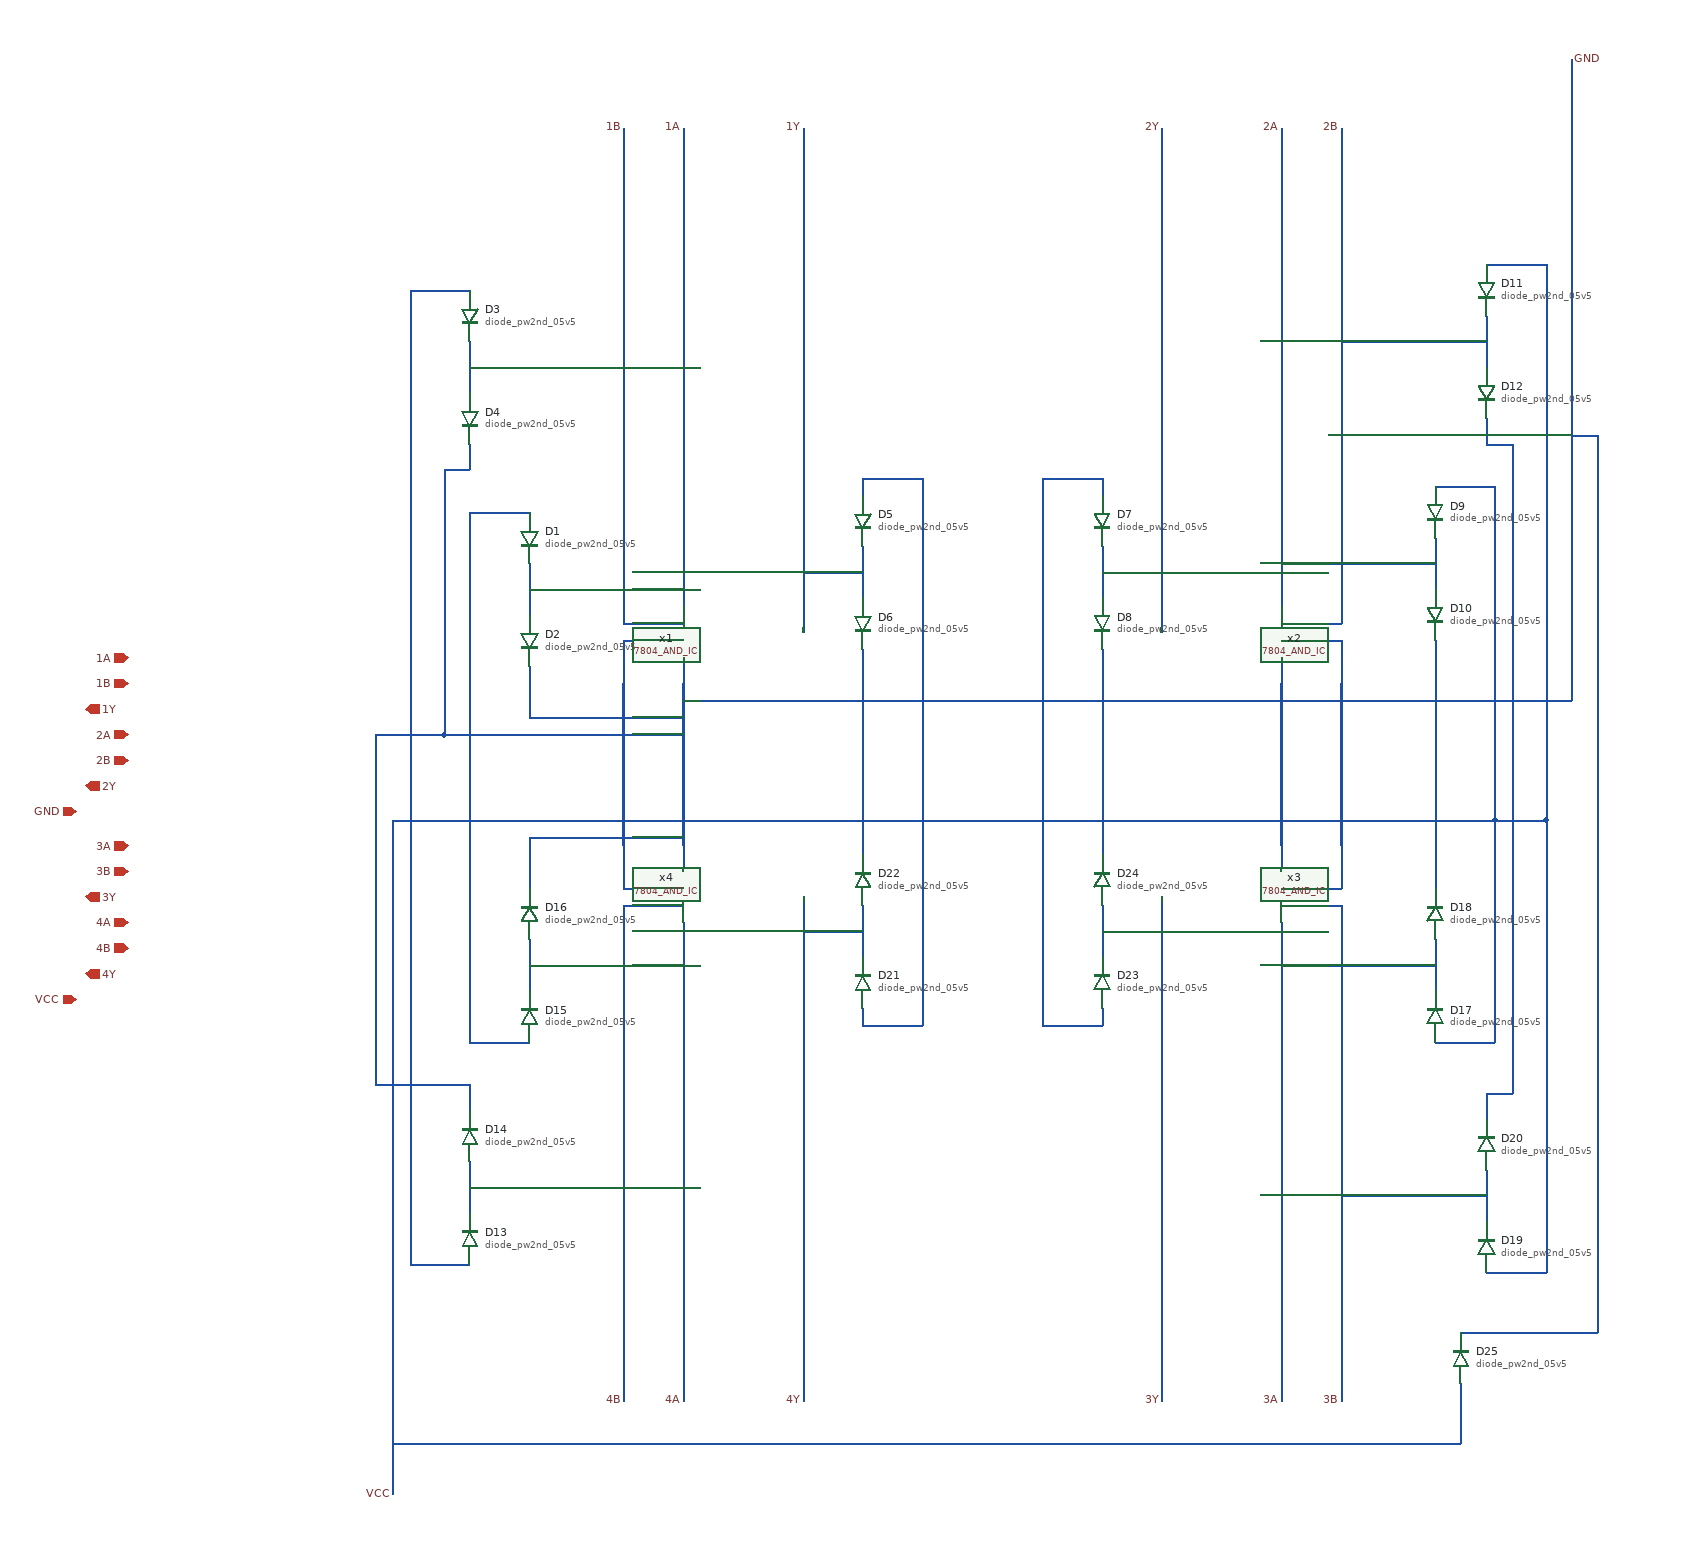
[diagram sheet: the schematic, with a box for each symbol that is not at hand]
v {xschem version=3.4.5 file_version=1.2
}
G {}
K {}
V {}
S {}
E {}
N -590 -970 -590 -520 {
lab=1A}
N -660 -500 -640 -500 {
lab=1B}
N -660 -970 -660 -500 {
lab=1B}
N -450 -970 -450 -490 {
lab=1Y}
N -590 -460 -590 -430 {
lab=GND}
N -660 -480 -640 -480 {
lab=VCC}
N -660 -480 -660 -430 {
lab=VCC}
N 110 -970 110 -520 {
lab=2A}
N 110 -500 180 -500 {
lab=2B}
N 180 -970 180 -500 {
lab=2B}
N 110 -460 110 -430 {
lab=GND}
N 110 -480 180 -480 {
lab=VCC}
N 180 -480 180 -430 {
lab=VCC}
N -30 -970 -30 -490 {
lab=2Y}
N 110 -240 110 -210 {
lab=GND}
N 110 -190 180 -190 {
lab=VCC}
N 180 -240 180 -190 {
lab=VCC}
N 110 -150 110 -120 {
lab=3A}
N 180 -170 180 -120 {
lab=3B}
N 110 -170 180 -170 {
lab=3B}
N -30 -180 -30 -120 {
lab=3Y}
N -450 -180 -450 300 {
lab=4Y}
N -590 -240 -590 -210 {
lab=GND}
N -660 -190 -640 -190 {
lab=VCC}
N -660 -240 -660 -190 {
lab=VCC}
N -590 -150 -590 300 {
lab=4A}
N -660 -170 -640 -170 {
lab=4B}
N -660 -170 -660 300 {
lab=4B}
N -590 -430 -590 -240 {bus=true
lab=GND}
N -660 -430 -660 -240 {bus=true
lab=VCC}
N 110 -430 110 -240 {bus=true
lab=GND}
N 180 -430 180 -240 {bus=true
lab=VCC}
N -930 -270 -930 300 {
lab=VCC}
N -930 -270 -870 -270 {
lab=VCC}
N 110 -410 250 -410 {
lab=GND}
N 450 -970 450 -410 {
lab=GND}
N -660 -1080 -660 -970 {
lab=1B}
N -590 -1080 -590 -970 {
lab=1A}
N -450 -1080 -450 -970 {
lab=1Y}
N -30 -1080 -30 -970 {
lab=2Y}
N 110 -1080 110 -970 {
lab=2A}
N 180 -1080 180 -970 {
lab=2B}
N 450 -1080 450 -970 {
lab=GND}
N -930 300 -930 410 {
lab=VCC}
N -660 300 -660 410 {
lab=4B}
N -590 300 -590 410 {
lab=4A}
N -450 300 -450 410 {
lab=4Y}
N -30 -120 -30 410 {
lab=3Y}
N 110 -120 110 410 {
lab=3A}
N 180 -120 180 410 {
lab=3B}
N -640 -500 -610 -500 {
lab=1B}
N -640 -480 -610 -480 {
lab=VCC}
N -640 -190 -610 -190 {
lab=VCC}
N -640 -170 -610 -170 {
lab=4B}
N -610 -500 -590 -500 {
lab=1B}
N -610 -480 -590 -480 {
lab=VCC}
N -610 -190 -590 -190 {
lab=VCC}
N -610 -170 -590 -170 {
lab=4B}
N -870 -270 -660 -270 {
lab=VCC}
N -660 -270 180 -270 {
lab=VCC}
N -590 -410 110 -410 {
lab=GND}
N -770 -570 -770 -510 {
lab=1A}
N -770 -540 -590 -540 {
lab=1A}
N -770 -450 -770 -390 {
lab=GND}
N -770 -390 -590 -390 {
lab=GND}
N -840 -630 -770 -630 {
lab=VCC}
N -840 -630 -840 -270 {
lab=VCC}
N -840 -830 -840 -770 {
lab=1B}
N -840 -800 -660 -800 {
lab=1B}
N -910 -890 -840 -890 {
lab=VCC}
N -910 -890 -910 -530 {
lab=VCC}
N -910 -530 -910 -270 {
lab=VCC}
N -840 -710 -840 -680 {
lab=GND}
N -870 -680 -840 -680 {
lab=GND}
N -870 -680 -870 -370 {
lab=GND}
N -380 -590 -380 -530 {
lab=1Y}
N -380 -470 -380 -410 {
lab=GND}
N -380 -670 -380 -650 {
lab=VCC}
N -380 -670 -310 -670 {
lab=VCC}
N -310 -670 -310 -270 {
lab=VCC}
N -100 -590 -100 -530 {
lab=2Y}
N -100 -470 -100 -410 {
lab=GND}
N -100 -670 -100 -650 {
lab=VCC}
N -170 -670 -100 -670 {
lab=VCC}
N -170 -670 -170 -270 {
lab=VCC}
N -100 -560 -30 -560 {
lab=2Y}
N -450 -560 -380 -560 {
lab=1Y}
N 290 -600 290 -540 {
lab=2A}
N 110 -570 290 -570 {
lab=2A}
N 290 -480 290 -420 {
lab=GND}
N 290 -660 360 -660 {
lab=VCC}
N 360 -660 360 -300 {
lab=VCC}
N 350 -860 350 -800 {
lab=2B}
N 350 -920 420 -920 {
lab=VCC}
N 420 -920 420 -570 {
lab=VCC}
N 420 -570 420 -310 {
lab=VCC}
N 350 -740 350 -710 {
lab=GND}
N 350 -710 380 -710 {
lab=GND}
N 380 -710 380 -410 {
lab=GND}
N 250 -410 450 -410 {
lab=GND}
N 360 -300 360 -270 {
lab=VCC}
N 180 -270 360 -270 {
lab=VCC}
N 290 -420 290 -410 {
lab=GND}
N -840 130 -840 190 {
lab=4B}
N -840 160 -660 160 {
lab=4B}
N -910 250 -840 250 {
lab=VCC}
N -910 -110 -910 250 {
lab=VCC}
N -840 40 -840 70 {
lab=GND}
N -870 40 -840 40 {
lab=GND}
N -770 -130 -770 -70 {
lab=4A}
N -770 -100 -590 -100 {
lab=4A}
N -770 -250 -770 -190 {
lab=GND}
N -840 -10 -770 -10 {
lab=VCC}
N 420 -310 420 -270 {
lab=VCC}
N 360 -270 420 -270 {
lab=VCC}
N 290 -130 290 -70 {
lab=3A}
N 110 -100 290 -100 {
lab=3A}
N 290 -250 290 -190 {
lab=GND}
N 290 -10 360 -10 {
lab=VCC}
N -770 -250 -590 -250 {
lab=GND}
N -840 -270 -840 -10 {
lab=VCC}
N 350 140 350 200 {
lab=3B}
N 350 260 420 260 {
lab=VCC}
N 420 -100 420 260 {
lab=VCC}
N 350 50 350 80 {
lab=GND}
N 350 50 380 50 {
lab=GND}
N 380 -260 380 50 {
lab=GND}
N -910 -270 -910 -110 {
lab=VCC}
N 290 -410 290 -250 {
lab=GND}
N 360 -270 360 -10 {
lab=VCC}
N 420 -270 420 -100 {
lab=VCC}
N 380 -410 380 -260 {
lab=GND}
N 180 170 350 170 {
lab=3B}
N 180 -830 350 -830 {
lab=2B}
N -380 -170 -380 -110 {
lab=4Y}
N -380 -290 -380 -230 {
lab=GND}
N -380 -50 -380 -30 {
lab=VCC}
N -380 -30 -310 -30 {
lab=VCC}
N -450 -140 -380 -140 {
lab=4Y}
N -380 -410 -380 -290 {
lab=GND}
N -310 -270 -310 -30 {
lab=VCC}
N -100 -170 -100 -110 {
lab=3Y}
N -100 -50 -100 -30 {
lab=VCC}
N -170 -30 -100 -30 {
lab=VCC}
N -100 -140 -30 -140 {
lab=3Y}
N -170 -270 -170 -30 {
lab=VCC}
N -100 -410 -100 -230 {
lab=GND}
N -870 -370 -590 -370 {
lab=GND}
N -950 -370 -870 -370 {
lab=GND}
N -950 40 -870 40 {
lab=GND}
N -950 -370 -950 40 {
lab=GND}
N 450 -1160 450 -1080 {
lab=GND}
N -930 410 -930 520 {
lab=VCC}
N 320 390 320 460 {
lab=VCC}
N -930 460 320 460 {
lab=VCC}
N 320 330 480 330 {
lab=GND}
N 480 -720 480 330 {
lab=GND}
N 450 -720 480 -720 {
lab=GND}
C {7804_AND_IC.sym} -510 -500 0 0 {name=x1 }
C {7804_AND_IC.sym} 30 -500 0 1 {name=x2}
C {7804_AND_IC.sym} 30 -170 2 0 {name=x3}
C {7804_AND_IC.sym} -510 -170 2 1 {name=x4}
C {devices/lab_pin.sym} 450 -1160 2 0 {name=p4 sig_type=std_logic lab=GND}
C {devices/lab_pin.sym} -930 520 0 0 {name=p5 sig_type=std_logic lab=VCC}
C {devices/lab_pin.sym} -590 -1080 1 0 {name=p18 sig_type=std_logic lab=1A}
C {devices/lab_pin.sym} -660 -1080 1 0 {name=p19 sig_type=std_logic lab=1B}
C {devices/lab_pin.sym} -450 -1080 1 0 {name=p20 sig_type=std_logic lab=1Y}
C {devices/lab_pin.sym} 110 -1080 3 1 {name=p21 sig_type=std_logic lab=2A}
C {devices/lab_pin.sym} 180 -1080 3 1 {name=p22 sig_type=std_logic lab=2B}
C {devices/lab_pin.sym} -30 -1080 3 1 {name=p23 sig_type=std_logic lab=2Y}
C {devices/lab_pin.sym} -660 410 1 1 {name=p24 sig_type=std_logic lab=4B}
C {devices/lab_pin.sym} -590 410 1 1 {name=p25 sig_type=std_logic lab=4A}
C {devices/lab_pin.sym} -450 410 1 1 {name=p26 sig_type=std_logic lab=4Y}
C {devices/lab_pin.sym} 180 410 3 0 {name=p27 sig_type=std_logic lab=3B}
C {devices/lab_pin.sym} 110 410 3 0 {name=p28 sig_type=std_logic lab=3A}
C {devices/lab_pin.sym} -30 410 3 0 {name=p29 sig_type=std_logic lab=3Y}
C {sky130_fd_pr/diode.sym} -770 -600 0 0 {name=D1
model=diode_pw2nd_05v5
area=1e12
pj=4e6
}
C {sky130_fd_pr/diode.sym} -770 -480 0 0 {name=D2
model=diode_pw2nd_05v5
area=1e12
pj=4e6
}
C {sky130_fd_pr/diode.sym} -840 -860 0 0 {name=D3
model=diode_pw2nd_05v5
area=1e12
pj=4e6
}
C {sky130_fd_pr/diode.sym} -840 -740 0 0 {name=D4
model=diode_pw2nd_05v5
area=1e12
pj=4e6
}
C {sky130_fd_pr/diode.sym} -380 -620 0 0 {name=D5
model=diode_pw2nd_05v5
area=1e12
pj=4e6
}
C {sky130_fd_pr/diode.sym} -380 -500 0 0 {name=D6
model=diode_pw2nd_05v5
area=1e12
pj=4e6
}
C {sky130_fd_pr/diode.sym} -100 -620 0 1 {name=D7
model=diode_pw2nd_05v5
area=1e12
pj=4e6
}
C {sky130_fd_pr/diode.sym} -100 -500 0 1 {name=D8
model=diode_pw2nd_05v5
area=1e12
pj=4e6
}
C {sky130_fd_pr/diode.sym} 290 -630 0 1 {name=D9
model=diode_pw2nd_05v5
area=1e12
pj=4e6
}
C {sky130_fd_pr/diode.sym} 290 -510 0 1 {name=D10
model=diode_pw2nd_05v5
area=1e12
pj=4e6
}
C {sky130_fd_pr/diode.sym} 350 -890 0 1 {name=D11
model=diode_pw2nd_05v5
area=1e12
pj=4e6
}
C {sky130_fd_pr/diode.sym} 350 -770 0 1 {name=D12
model=diode_pw2nd_05v5
area=1e12
pj=4e6
}
C {sky130_fd_pr/diode.sym} -840 220 2 1 {name=D13
model=diode_pw2nd_05v5
area=1e12
pj=4e6
}
C {sky130_fd_pr/diode.sym} -840 100 2 1 {name=D14
model=diode_pw2nd_05v5
area=1e12
pj=4e6
}
C {sky130_fd_pr/diode.sym} -770 -40 2 1 {name=D15
model=diode_pw2nd_05v5
area=1e12
pj=4e6
}
C {sky130_fd_pr/diode.sym} -770 -160 2 1 {name=D16
model=diode_pw2nd_05v5
area=1e12
pj=4e6
}
C {sky130_fd_pr/diode.sym} 290 -40 2 0 {name=D17
model=diode_pw2nd_05v5
area=1e12
pj=4e6
}
C {sky130_fd_pr/diode.sym} 290 -160 2 0 {name=D18
model=diode_pw2nd_05v5
area=1e12
pj=4e6
}
C {sky130_fd_pr/diode.sym} 350 230 2 0 {name=D19
model=diode_pw2nd_05v5
area=1e12
pj=4e6
}
C {sky130_fd_pr/diode.sym} 350 110 2 0 {name=D20
model=diode_pw2nd_05v5
area=1e12
pj=4e6
}
C {sky130_fd_pr/diode.sym} -380 -80 2 1 {name=D21
model=diode_pw2nd_05v5
area=1e12
pj=4e6
}
C {sky130_fd_pr/diode.sym} -380 -200 2 1 {name=D22
model=diode_pw2nd_05v5
area=1e12
pj=4e6
}
C {sky130_fd_pr/diode.sym} -100 -80 2 0 {name=D23
model=diode_pw2nd_05v5
area=1e12
pj=4e6
}
C {sky130_fd_pr/diode.sym} -100 -200 2 0 {name=D24
model=diode_pw2nd_05v5
area=1e12
pj=4e6
}
C {sky130_fd_pr/diode.sym} 320 360 2 1 {name=D25
model=diode_pw2nd_05v5
area=100e12
pj=400e6
}
C {devices/ipin.sym} -1240 -460 0 0 {name=p1 lab=1A}
C {devices/iopin.sym} -1300 -280 0 0 {name=p2 lab=GND}
C {devices/opin.sym} -1290 -400 0 0 {name=p3 lab=1Y}
C {devices/ipin.sym} -1240 -430 0 0 {name=p6 lab=1B}
C {devices/ipin.sym} -1240 -370 0 0 {name=p7 lab=2A}
C {devices/ipin.sym} -1240 -340 0 0 {name=p8 lab=2B}
C {devices/ipin.sym} -1240 -240 0 0 {name=p9 lab=3A}
C {devices/ipin.sym} -1240 -210 0 0 {name=p10 lab=3B}
C {devices/ipin.sym} -1240 -150 0 0 {name=p11 lab=4A}
C {devices/ipin.sym} -1240 -120 0 0 {name=p12 lab=4B}
C {devices/opin.sym} -1290 -310 0 0 {name=p13 lab=2Y}
C {devices/opin.sym} -1290 -180 0 0 {name=p14 lab=3Y}
C {devices/opin.sym} -1290 -90 0 0 {name=p15 lab=4Y}
C {devices/iopin.sym} -1300 -60 0 0 {name=p16 lab=VCC}
